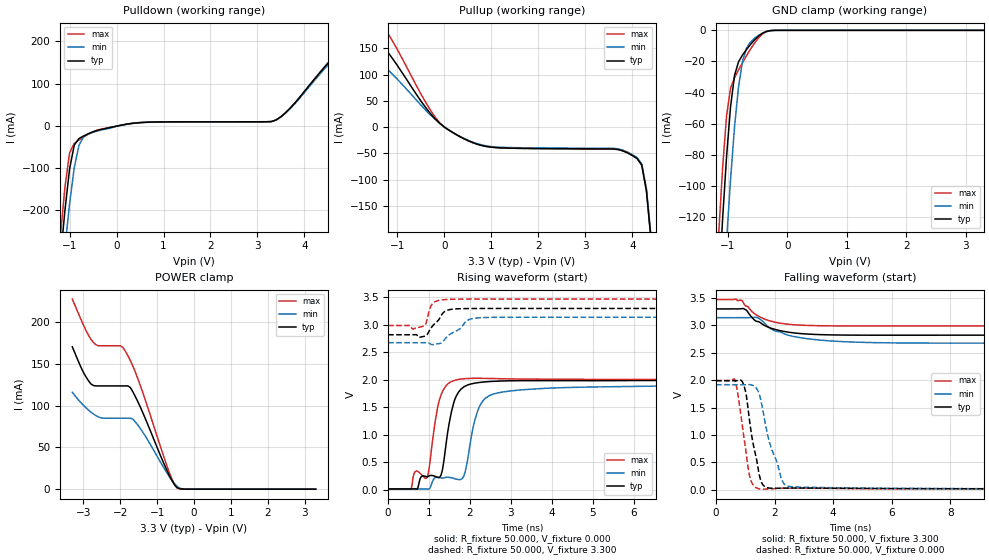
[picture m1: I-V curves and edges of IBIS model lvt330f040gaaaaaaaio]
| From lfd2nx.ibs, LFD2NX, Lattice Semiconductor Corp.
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[Model] lvt330f040gaaaaaaaio
Model_type I/O
Polarity   Non-Inverting
Enable   Active-Low
Vinl =  0.800V
Vinh =  2.000V
Vmeas =  1.650V
Cref =  0.0F
Rref =  1.000M
Vref =  0.0V
C_comp   5.000pF   4.000pF   5.500pF
[Temperature Range]   25.000   0.125k   -40.000
[Voltage Range]   3.300V   3.140V   3.470V
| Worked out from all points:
|   slope of the pulldown table from 0 to 0.495 V, typ, clamps not added: 58.8 ohm
|   slope of the pullup table from 0 to 0.495 V, typ, clamps not added: 19.5 ohm
|   GND clamp passes 1 mA (typ) near -0.37 V on its own axis
|   POWER clamp passes 1 mA (typ) near -0.42 V on its own axis
|   rising waveform, R_fixture 50.000, V_fixture 0.000: 20-80 % time 269ps typ, 342ps min, 236ps max; typ from 0.019 V to 1.99 V
|   rising waveform, R_fixture 50.000, V_fixture 3.300: 20-80 % time 301ps typ, 462ps min, 125ps max; typ from 2.82 V to 3.3 V
|   falling waveform, R_fixture 50.000, V_fixture 3.300: 20-80 % time 937ps typ, 1.3ns min, 836ps max; typ from 3.3 V to 2.82 V
|   falling waveform, R_fixture 50.000, V_fixture 0.000: 20-80 % time 363ps typ, 566ps min, 307ps max; typ from 1.99 V to 0.019 V
[GND_clamp]
|Voltage   I(typ)   I(min)   I(max)
-3.3V     -1.887A    -1.873A    -1.902A
-1.156V   -166.9mA   -224mA     -132.1mA
-1.089V   -121.5mA   -178.4mA   -88.64mA
-1.022V   -81.05mA   -135.2mA   -54.94mA
-955mV    -48.98mA   -95.79mA   -37.15mA
-888mV    -28.98mA   -62.05mA   -30.42mA
-821mV    -20.23mA   -36.35mA   -25.49mA
-754mV    -15.89mA   -19.89mA   -20.81mA
-687mV    -12.34mA   -11.44mA   -16.31mA
-620mV    -9.094mA   -7.515mA   -12.09mA
-419mV    -1.869mA   -1.836mA   -2.383mA
3.3V      0A         0A         0A
[POWER_clamp]
|Voltage   I(typ)   I(min)   I(max)
-3.3V     170.3mA    115.9mA    227.4mA
-2.998V   139.6mA    100.3mA    196.3mA
-2.797V   125.9mA    92.2mA     179.4mA
-2.596V   123.5mA    86.45mA    171.5mA
-1.993V   123.5mA    84.93mA    171.5mA
-1.792V   123.5mA    84.93mA    159.6mA
-1.658V   116.4mA    83.68mA    147.1mA
-1.457V   98.28mA    72.65mA    124.1mA
-720mV    21.08mA    18.41mA    25.96mA
-452mV    1.573mA    3.148mA    1.229mA
-184mV    5.589uA    37.85uA    1.612uA
3.3V      0A         0A         0A
[Pulldown]
|Voltage   I(typ)   I(min)   I(max)
-3.3V     -3.199A    -3.09A     -3.287A
-1.2V     -321.9mA   -406.6mA   -267.9mA
-1.1V     -202.3mA   -291.4mA   -147.1mA
-1V       -102.6mA   -185.6mA   -64.5mA
-900mV    -45.82mA   -99.21mA   -41.48mA
-800mV    -30.11mA   -46.44mA   -33.69mA
-600mV    -18.75mA   -19.13mA   -19.91mA
500mV     7.634mA    7.405mA    7.634mA
3.3V      10.2mA     9.896mA    10.2mA
5V        196.9mA    191mA      196.9mA
6.3V      206.6mA    200.4mA    206.6mA
6.6V      235mA      227.9mA    235mA
[Pullup]
|Voltage   I(typ)   I(min)   I(max)
-3.3V     225.4mA    159.2mA    289.5mA
-3V       191.7mA    142.3mA    256.1mA
-2.6V     172mA      126.6mA    227.2mA
-1.5V     172mA      125.1mA    215.9mA
-1.3V     153.8mA    116.5mA    191.8mA
-200mV    15.97mA    14.98mA    19.28mA
600mV     -29.35mA   -28.47mA   -29.35mA
3.9V      -49.03mA   -47.55mA   -49.03mA
4.2V      -72.01mA   -69.85mA   -72.01mA
4.3V      -121mA     -117.4mA   -121mA
4.4V      -215.8mA   -209.3mA   -215.8mA
6.6V      -3.209A    -3.112A    -3.209A
[Ramp]
| variable   typ   min   max
dV/dt_r   1.182/0.275n   1.138/0.343n   1.192/0.237n
dV/dt_f   0.287/0.944n   0.277/1.301n   0.288/0.844n
R_load = 50.000
[Rising Waveform]
R_fixture = 50.000
V_fixture = 0.000
V_fixture_min = 0.000
V_fixture_max = 0.000
|  time   V(typ)   V(min)   V(max)
0s        19.23mV    18.96mV    17.33mV
950ps     239.8mV    19.5mV     227.4mV
1.27ns    240mV      224.2mV    1.673V
1.63ns    1.645V     205.4mV    1.994V
1.85ns    1.874V     257.1mV    2.022V
2.07ns    1.935V     1.113V     2.03V
2.32ns    1.962V     1.624V     2.03V
2.78ns    1.981V     1.779V     2.022V
8.46ns    1.994V     1.902V     2.008V
200ns     1.989V     1.916V     1.996V
[Rising Waveform]
R_fixture = 50.000
V_fixture = 3.300
V_fixture_min = 3.140
V_fixture_max = 3.470
|  time   V(typ)   V(min)   V(max)
0s        2.822V     2.678V     2.99V
530ps     2.822V     2.678V     2.992V
600ps     2.822V     2.678V     2.925V
880ps     2.792V     2.678V     2.982V
930ps     2.807V     2.678V     3.04V
1.05ns    2.945V     2.647V     3.349V
1.28ns    3.148V     2.666V     3.451V
1.45ns    3.268V     2.793V     3.463V
1.96ns    3.298V     3.091V     3.47V
200ns     3.3V       3.14V      3.47V
[Falling Waveform]
R_fixture = 50.000
V_fixture = 3.300
V_fixture_min = 3.140
V_fixture_max = 3.470
|  time   V(typ)   V(min)   V(max)
0s        3.3V       3.14V      3.47V
680ps     3.3V       3.139V     3.479V
870ps     3.304V     3.141V     3.457V
950ps     3.303V     3.141V     3.398V
1.44ns    3.068V     3.134V     3.17V
1.99ns    2.929V     2.903V     3.061V
2.79ns    2.855V     2.783V     3.007V
4.09ns    2.825V     2.71V      2.99V
8.26ns    2.821V     2.675V     2.99V
200ns     2.822V     2.678V     2.99V
[Falling Waveform]
R_fixture = 50.000
V_fixture = 0.000
V_fixture_min = 0.000
V_fixture_max = 0.000
|  time   V(typ)   V(min)   V(max)
0s        1.99V      1.916V     1.996V
640ps     1.99V      1.915V     2.01V
910ps     1.961V     1.916V     1.125V
1.2ns     1.056V     1.916V     159.1mV
1.43ns    415.4mV    1.806V     24.54mV
1.6ns     93.72mV    1.453V     12.06mV
1.83ns    31.38mV    857.1mV    16.57mV
2.32ns    30.7mV     107.4mV    29.64mV
4.53ns    26.53mV    35.5mV     22.52mV
200ns     18.98mV    18.96mV    17.12mV
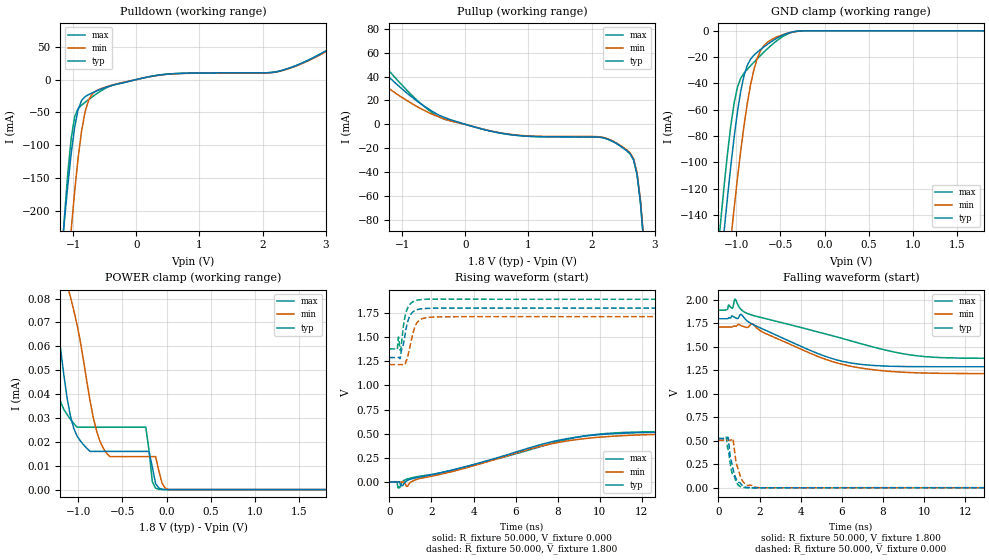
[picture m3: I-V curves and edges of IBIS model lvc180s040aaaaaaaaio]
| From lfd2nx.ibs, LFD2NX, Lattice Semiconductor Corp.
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[Model] lvc180s040aaaaaaaaio
Model_type I/O
Polarity   Non-Inverting
Enable   Active-Low
Vinl =  0.630V
Vinh =  1.170V
Vmeas =  0.900V
Cref =  0.0F
Rref =  1.000M
Vref =  0.0V
C_comp   5.000pF   4.000pF   5.500pF
[Temperature Range]   25.000   0.125k   -40.000
[Voltage Range]   1.800V   1.710V   1.890V
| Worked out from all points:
|   slope of the pulldown table from 0 to 0.27 V, typ, clamps not added: 48.7 ohm
|   slope of the pullup table from 0 to 0.27 V, typ, clamps not added: 66.8 ohm
|   GND clamp passes 1 mA (typ) near -0.37 V on its own axis
|   rising waveform, R_fixture 50.000, V_fixture 0.000: 20-80 % time 5.14ns typ, 5.06ns min, 5.46ns max; typ from 0 V to 0.523 V
|   rising waveform, R_fixture 50.000, V_fixture 1.800: 20-80 % time 317ps typ, 338ps min, 247ps max; typ from 1.29 V to 1.8 V
|   falling waveform, R_fixture 50.000, V_fixture 1.800: 20-80 % time 3.23ns typ, 3.42ns min, 5.34ns max; typ from 1.8 V to 1.29 V
|   falling waveform, R_fixture 50.000, V_fixture 0.000: 20-80 % time 309ps typ, 328ps min, 349ps max; typ from 0.523 V to 0 V
[GND_clamp]
|Voltage   I(typ)   I(min)   I(max)
-1.8V     -665.5mA   -701.9mA   -644.7mA
-1.208V   -203.2mA   -259.3mA   -168.6mA
-1.171V   -176.5mA   -233.3mA   -141.8mA
-1.134V   -150.7mA   -207.7mA   -116.3mA
-1.06V    -102.3mA   -158.3mA   -71.8mA
-1.023V   -80.78mA   -134.8mA   -54.83mA
-986mV    -61.78mA   -112.4mA   -42.93mA
-875mV    -26.33mA   -55.53mA   -29.29mA
-764mV    -16.38mA   -21.41mA   -21.4mA
-616mV    -8.858mA   -7.288mA   -11.79mA
-283mV    -142.7uA   -287uA     -113.6uA
1.8V      1.806nA    0A         -451.7pA
[POWER_clamp]
|Voltage   I(typ)   I(min)   I(max)
-1.8V     186.1uA    259.3uA    183.5uA
-1.382V   94.44uA    136.9uA    91.49uA
-1.345V   89.56uA    127.8uA    77.5uA
-1.308V   84.02uA    119.2uA    62.8uA
-1.234V   68.87uA    103.6uA    41.99uA
-1.086V   30.66uA    80.57uA    29.36uA
-864mV    15.99uA    36.92uA    26.17uA
-642mV    15.99uA    13.83uA    26.17uA
-235mV    15.99uA    13.83uA    26.17uA
-161mV    9.477uA    13.83uA    3.316uA
24mV      0A         0A         261.1pA
1.8V      0A         0A         0A
[Pulldown]
|Voltage   I(typ)   I(min)   I(max)
-1.8V     -995.9mA   -1.248A    -1.252A
-1.195V   -277.5mA   -429.4mA   -291.1mA
-1.14V    -218.4mA   -360mA     -213.9mA
-1.03V    -112.8mA   -229.5mA   -89.71mA
-975mV    -72.73mA   -170.7mA   -56.82mA
-920mV    -45.76mA   -119.3mA   -44.24mA
-865mV    -31.82mA   -78.24mA   -38.99mA
-755mV    -23mA      -31.77mA   -30.61mA
-535mV    -13.67mA   -13.02mA   -15.89mA
290mV     5.876mA    5.699mA    5.876mA
2.27V     13.04mA    12.65mA    13.04mA
3.6V      77.31mA    74.99mA    77.31mA
[Pullup]
|Voltage   I(typ)   I(min)   I(max)
-1.8V     69.64mA    52.58mA    81.3mA
-910mV    25.55mA    19.41mA    27.74mA
-415mV    7.654mA    6.149mA    6.163mA
630mV     -8.033mA   -7.792mA   -8.033mA
2.115V    -10.77mA   -10.45mA   -10.77mA
2.335V    -14.38mA   -13.95mA   -14.38mA
2.555V    -22.02mA   -21.36mA   -22.02mA
2.665V    -29.69mA   -28.8mA    -29.69mA
2.72V     -41.99mA   -40.73mA   -41.99mA
2.775V    -65.96mA   -63.98mA   -65.96mA
2.83V     -101.9mA   -98.8mA    -101.9mA
3.6V      -893.2mA   -866.4mA   -893.2mA
[Ramp]
| variable   typ   min   max
dV/dt_r   0.314/5.142n   0.305/5.063n   0.315/5.456n
dV/dt_f   0.307/3.233n   0.292/3.426n   0.308/5.337n
R_load = 50.000
[Rising Waveform]
R_fixture = 50.000
V_fixture = 0.000
V_fixture_min = 0.000
V_fixture_max = 0.000
|  time   V(typ)   V(min)   V(max)
0s        55.76uV    -541.6uV   144.1uV
354ps     -420nV     -811uV     1.746mV
407ps     201.3uV    -848.3uV   -58.2mV
481ps     -1.924mV   -614.8uV   -59.5mV
609ps     -39.04mV   -345uV     -460uV
844ps     15.36mV    -45.3mV    31.01mV
1.355ns   47.73mV    31.55mV    56.92mV
7ns       375.4mV    360.4mV    354.7mV
9.719ns   485.6mV    459.1mV    489.7mV
20ns      522.7mV    504.7mV    524.5mV
[Rising Waveform]
R_fixture = 50.000
V_fixture = 1.800
V_fixture_min = 1.710
V_fixture_max = 1.890
|  time   V(typ)   V(min)   V(max)
0s        1.289V     1.215V     1.378V
371ps     1.289V     1.215V     1.375V
429ps     1.289V     1.215V     1.501V
520ps     1.29V      1.215V     1.362V
744ps     1.527V     1.215V     1.716V
859ps     1.652V     1.291V     1.798V
998ps     1.73V      1.427V     1.845V
1.214ns   1.775V     1.608V     1.875V
1.504ns   1.792V     1.686V     1.888V
20ns      1.8V       1.712V     1.892V
[Falling Waveform]
R_fixture = 50.000
V_fixture = 1.800
V_fixture_min = 1.710
V_fixture_max = 1.890
|  time   V(typ)   V(min)   V(max)
0s        1.8V       1.712V     1.892V
674ps     1.829V     1.713V     1.912V
811ps     1.812V     1.721V     2.009V
1.1ns     1.846V     1.727V     1.898V
1.492ns   1.761V     1.72V      1.848V
1.652ns   1.741V     1.745V     1.837V
5.003ns   1.415V     1.384V     1.649V
6.83ns    1.316V     1.278V     1.54V
10.47ns   1.289V     1.22V      1.39V
20ns      1.289V     1.215V     1.378V
[Falling Waveform]
R_fixture = 50.000
V_fixture = 0.000
V_fixture_min = 0.000
V_fixture_max = 0.000
|  time   V(typ)   V(min)   V(max)
0s        522.7mV    504.7mV    524.5mV
367ps     522.3mV    504.3mV    540mV
472ps     530.7mV    504.4mV    405.7mV
580ps     321.1mV    504.8mV    244.9mV
694ps     214.1mV    521.9mV    135.5mV
872ps     87.55mV    253.7mV    60.07mV
1.082ns   43.07mV    111.3mV    10.88mV
1.262ns   10.06mV    46.43mV    1.455mV
2.193ns   -442.4uV   -843.4uV   -1.377mV
20ns      55.76uV    -541.6uV   144.1uV
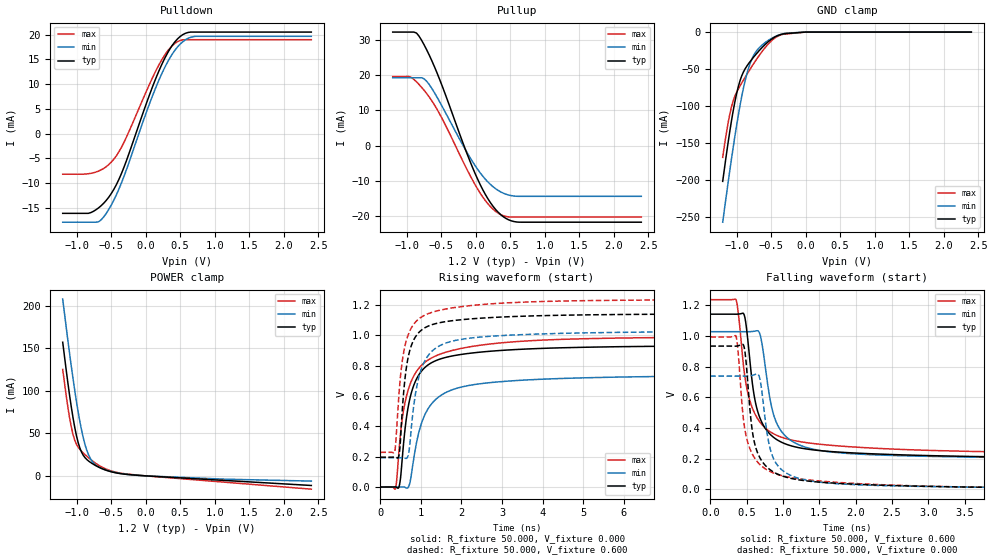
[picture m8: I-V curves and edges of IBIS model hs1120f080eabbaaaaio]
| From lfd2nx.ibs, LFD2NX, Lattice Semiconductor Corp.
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|Model hs1120f080eabbaaaaio
[Model] hs1120f080eabbaaaaio
| Clamp models do not include dynamic input termination. Please refer to
| the hs1120axxxeabbaaaain model for input termination.
Model_type I/O
Polarity   Non-Inverting
Enable   Active-Low
Vinl =  0.500V
Vinh =  0.700V
Vmeas =  0.600V
Cref =  20.000pF
Rref =  50.000
Vref =  0.600V
C_comp   5.000pF   4.000pF   5.500pF
[Temperature Range]   25.000   0.125k   -40.000
[Voltage Range]   1.200V   1.140V   1.260V
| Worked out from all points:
|   slope of the pulldown table from 0 to 0.18 V, typ, clamps not added: 27.3 ohm
|   slope of the pullup table from 0 to 0.18 V, typ, clamps not added: 26.1 ohm
|   GND clamp passes 1 mA (typ) near -0.14 V on its own axis
|   POWER clamp passes 1 mA (typ) near -0.17 V on its own axis
|   rising waveform, R_fixture 50.000, V_fixture 0.000: 20-80 % time 431ps typ, 626ps min, 545ps max; typ from 0 V to 0.934 V
|   rising waveform, R_fixture 50.000, V_fixture 0.600: 20-80 % time 284ps typ, 413ps min, 327ps max; typ from 0.197 V to 1.14 V
|   falling waveform, R_fixture 50.000, V_fixture 0.600: 20-80 % time 253ps typ, 270ps min, 285ps max; typ from 1.14 V to 0.197 V
|   falling waveform, R_fixture 50.000, V_fixture 0.000: 20-80 % time 198ps typ, 218ps min, 217ps max; typ from 0.934 V to 0 V
[Pulldown]
|Voltage   I(typ)   I(min)   I(max)
-1.2V     -16.15mA   -17.94mA   -8.219mA
-793mV    -16mA      -17.94mA   -8.053mA
-682mV    -15.05mA   -17.87mA   -7.595mA
-571mV    -13.55mA   -16.18mA   -6.715mA
-460mV    -11.3mA    -13.49mA   -5.195mA
-349mV    -8.077mA   -9.972mA   -2.767mA
21mV      6.472mA    4.689mA    8.875mA
206mV     13.1mA     11.24mA    14.23mA
354mV     17.17mA    15.36mA    17.32mA
502mV     19.67mA    18.13mA    18.86mA
724mV     20.55mA    19.68mA    19.01mA
2.4V      20.55mA    19.69mA    19.01mA
[Pullup]
|Voltage   I(typ)   I(min)   I(max)
-1.2V     32.18mA    19.26mA    19.61mA
-930mV    32.18mA    19.26mA    19.34mA
-856mV    31.91mA    19.26mA    18.1mA
-782mV    29.87mA    19.26mA    16.56mA
-671mV    25.67mA    17.33mA    13.8mA
-523mV    18.91mA    12.54mA    9.103mA
-153mV    -749.4uA   -894uA     -5.584mA
32mV      -9.535mA   -6.72mA    -12.3mA
217mV     -16.14mA   -10.96mA   -17.24mA
402mV     -20.07mA   -13.4mA    -19.78mA
624mV     -21.6mA    -14.29mA   -20.15mA
2.4V      -21.61mA   -14.29mA   -20.15mA
[GND_clamp]
|Voltage   I(typ)   I(min)   I(max)
-1.2V     -201.8mA   -257mA     -169.4mA
-1.125V   -151.4mA   -205.6mA   -124.4mA
-1.05V    -107.4mA   -157mA     -93.36mA
-975mV    -74.07mA   -112.9mA   -77.04mA
-925mV    -59.28mA   -87.24mA   -68.87mA
-875mV    -49.6mA    -65.58mA   -61.06mA
-825mV    -42.58mA   -48.49mA   -53.44mA
-750mV    -33.57mA   -31.23mA   -42.41mA
-600mV    -18.06mA   -15.21mA   -22.68mA
-375mV    -3.74mA    -3.594mA   -4.332mA
0V        0A         0A         0A
2.4V      0A         0A         0A
[POWER_clamp]
|Voltage   I(typ)   I(min)   I(max)
-1.2V     156.9mA    207.6mA    125mA
-1.125V   109.1mA    159mA      80.51mA
-1.075V   80.57mA    128.3mA    57.13mA
-1.025V   56.63mA    99.87mA    41.73mA
-975mV    38.74mA    74.4mA     33.51mA
-900mV    23.86mA    43.88mA    26.68mA
-850mV    19.08mA    29.7mA     22.97mA
-775mV    14.57mA    17.25mA    17.9mA
-700mV    11.09mA    11.42mA    13.53mA
-450mV    3.875mA    4.163mA    4.676mA
-125mV    735.3uA    624.3uA    974.1uA
2.4V      -11.3mA    -6.156mA   -15.63mA
[Ramp]
| variable   typ   min   max
dV/dt_r   0.560/0.431n   0.443/0.629n   0.596/0.546n
dV/dt_f   0.523/0.375n   0.493/0.385n   0.533/0.474n
R_load = 50.000
[Rising Waveform]
R_fixture = 50.000
V_fixture = 0.000
V_fixture_min = 0.000
V_fixture_max = 0.000
|  time   V(typ)   V(min)   V(max)
0s        56.54uV    72.08uV    44.61uV
371ps     901.7uV    136.4uV    -12.4mV
457ps     -1.722mV   158.3uV    224.4mV
557ps     236.2mV    722.1uV    476.9mV
706ps     552.5mV    7.419mV    654.7mV
906ps     718.1mV    308.4mV    766.2mV
1.086ns   783.5mV    468.4mV    818.2mV
1.386ns   834mV      581.6mV    865.5mV
2.566ns   890.7mV    683.4mV    937.2mV
30ns      934.1mV    738.4mV    994mV
[Rising Waveform]
R_fixture = 50.000
V_fixture = 0.600
V_fixture_min = 0.571
V_fixture_max = 0.631
|  time   V(typ)   V(min)   V(max)
0s        196.7mV    192.5mV    228.3mV
354ps     197.1mV    192.6mV    229.9mV
457ps     203.8mV    192.7mV    596.5mV
617ps     732.4mV    189.4mV    938.4mV
697ps     866.1mV    218.9mV    1.008V
767ps     932.5mV    394mV      1.048V
917ps     1.007V     684.5mV    1.099V
1.147ns   1.055V     853mV      1.138V
2.081ns   1.104V     976mV      1.19V
30ns      1.143V     1.028V     1.238V
[Falling Waveform]
R_fixture = 50.000
V_fixture = 0.600
V_fixture_min = 0.571
V_fixture_max = 0.631
|  time   V(typ)   V(min)   V(max)
0s        1.143V     1.028V     1.238V
356ps     1.142V     1.028V     1.235V
466ps     1.139V     1.028V     768.9mV
607ps     601.2mV    1.031V     498.5mV
670ps     481mV      1.027V     446.3mV
721ps     425.1mV    919.6mV    416mV
851ps     346mV      520.8mV    366.7mV
990ps     304.1mV    369.9mV    337.5mV
1.88ns    238.8mV    233.5mV    278.2mV
30ns      196.7mV    192.5mV    228.3mV
[Falling Waveform]
R_fixture = 50.000
V_fixture = 0.000
V_fixture_min = 0.000
V_fixture_max = 0.000
|  time   V(typ)   V(min)   V(max)
0s        934.1mV    738.4mV    994mV
356ps     933.9mV    738mV      995.9mV
456ps     941.8mV    738.1mV    457mV
486ps     860.9mV    737.8mV    363.5mV
576ps     386.5mV    742.7mV    231.1mV
660ps     226.7mV    748.4mV    172mV
801ps     134.9mV    311.1mV    120.4mV
910ps     101.7mV    165.5mV    98.61mV
1.751ns   38.07mV    35.24mV    44.32mV
30ns      56.54uV    72.08uV    44.61uV
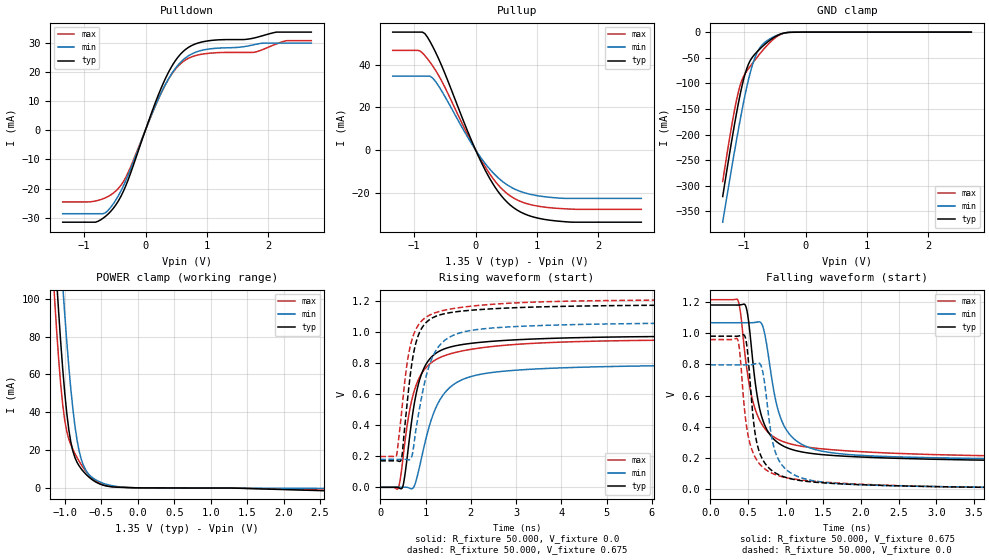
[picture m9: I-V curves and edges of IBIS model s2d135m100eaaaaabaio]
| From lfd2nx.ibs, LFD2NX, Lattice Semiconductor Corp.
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|Model s2d135m100eaaaaabaio
[Model] s2d135m100eaaaaabaio
Model_type I/O
Polarity   Non-Inverting
Enable   Active-Low
Vinl =  0.575V
Vinh =  0.775V
Vmeas =  0.675V
Cref =  30.000pF
Rref =  50.000
Vref =  0.675V
C_comp   5.000pF   4.000pF   5.500pF
[Temperature Range]   25.000   0.125k   -40.000
[Voltage Range]   1.350V   1.280V   1.420V
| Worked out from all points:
|   slope of the pulldown table from 0 to 0.203 V, typ, clamps not added: 17.4 ohm
|   slope of the pullup table from 0 to 0.203 V, typ, clamps not added: 16.9 ohm
|   GND clamp passes 1 mA (typ) near -0.31 V on its own axis
|   POWER clamp passes 1 mA (typ) near -0.43 V on its own axis
|   rising waveform, R_fixture 50.000, V_fixture 0.0: 20-80 % time 397ps typ, 623ps min, 491ps max; typ from 0 V to 0.981 V
|   rising waveform, R_fixture 50.000, V_fixture 0.675: 20-80 % time 303ps typ, 464ps min, 333ps max; typ from 0.171 V to 1.18 V
|   falling waveform, R_fixture 50.000, V_fixture 0.675: 20-80 % time 230ps typ, 281ps min, 276ps max; typ from 1.18 V to 0.172 V
|   falling waveform, R_fixture 50.000, V_fixture 0.0: 20-80 % time 176ps typ, 212ps min, 199ps max; typ from 0.981 V to 0 V
[Pulldown]
|Voltage   I(typ)   I(min)   I(max)
-1.35V    -31.52mA   -28.61mA   -24.57mA
-817mV    -31.52mA   -28.61mA   -24.26mA
-653mV    -29.52mA   -28.27mA   -23.15mA
-489mV    -25.73mA   -24.06mA   -20.91mA
-284mV    -17.01mA   -15.39mA   -14.5mA
290mV     16.19mA    14.33mA    14.27mA
454mV     22.83mA    20.27mA    20.05mA
659mV     27.8mA     24.92mA    24.18mA
1.069V    30.75mA    27.92mA    26.43mA
1.766V    31.59mA    29.29mA    26.68mA
2.299V    33.62mA    29.85mA    30.69mA
2.7V      33.62mA    29.85mA    30.69mA
[Pullup]
|Voltage   I(typ)   I(min)   I(max)
-1.35V    55.32mA    34.66mA    46.74mA
-908mV    55.32mA    34.66mA    46.54mA
-785mV    52.99mA    34.66mA    42.83mA
-703mV    48.79mA    33.84mA    39.62mA
-621mV    43.98mA    30.83mA    35.9mA
-88mV     5.888mA    4.039mA    4.858mA
117mV     -7.248mA   -4.887mA   -6.056mA
363mV     -19.41mA   -12.97mA   -16.28mA
609mV     -26.91mA   -17.99mA   -22.42mA
896mV     -31.1mA    -20.88mA   -25.7mA
1.265V    -33.2mA    -22.4mA    -27.29mA
2.7V      -33.94mA   -22.78mA   -27.9mA
[GND_clamp]
|Voltage   I(typ)   I(min)   I(max)
-1.35V    -320.9mA   -371mA     -291.7mA
-1.21V    -216.8mA   -269.5mA   -187.2mA
-1.126V   -159mA     -211.3mA   -133.3mA
-1.07V    -124.2mA   -174.2mA   -105.6mA
-986mV    -81.78mA   -122.8mA   -81.18mA
-902mV    -55.61mA   -79.36mA   -66.72mA
-818mV    -41.95mA   -47.73mA   -53.44mA
-734mV    -31.67mA   -28.77mA   -40.78mA
-650mV    -22.47mA   -18.69mA   -29.01mA
-454mV    -6.221mA   -5.753mA   -7.69mA
-286mV    -734.4uA   -759.2uA   -785.5uA
2.7V      0A         0A         0A
[POWER_clamp]
|Voltage   I(typ)   I(min)   I(max)
-1.35V    276.5mA    320.5mA    251mA
-1.142V   128.3mA    176.6mA    100.9mA
-1.114V   110.5mA    158.5mA    83.9mA
-1.086V   93.5mA     140.9mA    68.53mA
-1.03V    63.21mA    107.6mA    44.18mA
-1.002V   50.42mA    92.11mA    35.83mA
-946mV    30.82mA    64.28mA    25.76mA
-834mV    13.57mA    25.52mA    16.1mA
-750mV    8.839mA    12.31mA    10.8mA
-610mV    3.896mA    5.035mA    4.505mA
-78mV     75.17uA    92.3uA     98.29uA
2.7V      -1.695mA   -291.3uA   -1.333mA
[Ramp]
| variable   typ   min   max
dV/dt_r   0.588/0.398n   0.478/0.627n   0.576/0.491n
dV/dt_f   0.587/0.340n   0.536/0.410n   0.587/0.469n
R_load = 50.000
[Rising Waveform]
R_fixture= 50.000
V_fixture= 0.0
V_fixture_min= 0.0
V_fixture_max= 0.0
|time   V(typ)   V(min)   V(max)
0s        5.449uV    216.2uV    716.2nV
388ps     236.2uV    246.9uV    -9.1mV
497ps     4.218mV    457.3uV    176.6mV
716ps     473.8mV    -6.764mV   586.6mV
866ps     690.8mV    130.8mV    709.4mV
1.046ns   810.6mV    356.2mV    784mV
1.412ns   893.1mV    605.5mV    848.8mV
2.106ns   932.7mV    722.8mV    895.3mV
7.414ns   975.6mV    788.7mV    952.2mV
30ns      980.8mV    796.6mV    959.3mV
[Rising Waveform]
R_fixture= 50.000
V_fixture= 0.675
V_fixture_min= 0.642
V_fixture_max= 0.710
|time   V(typ)   V(min)   V(max)
0s        171.1mV    180.5mV    198.9mV
351ps     171.5mV    180.5mV    199.5mV
467ps     183.8mV    180.6mV    473.2mV
578ps     497.9mV    179.5mV    769.7mV
687ps     778.3mV    191.6mV    939.6mV
797ps     942.3mV    390.4mV    1.026V
1.147ns   1.093V     836.3mV    1.119V
1.724ns   1.135V     993.5mV    1.159V
6.767ns   1.176V     1.06V      1.209V
30ns      1.181V     1.067V     1.215V
[Falling Waveform]
R_fixture= 50.000
V_fixture= 0.675
V_fixture_min= 0.642
V_fixture_max= 0.710
|time   V(typ)   V(min)   V(max)
0s        1.181V     1.068V     1.215V
362ps     1.181V     1.068V     1.216V
406ps     1.183V     1.068V     1.114V
467ps     1.179V     1.068V     837.2mV
630ps     578.2mV    1.073V     469.4mV
737ps     395.6mV    960.1mV    381.6mV
864ps     311.5mV    579.6mV    329.2mV
994ps     271.1mV    393.4mV    300.7mV
1.654ns   215.5mV    231mV      251.7mV
30ns      171.7mV    181.2mV    199.4mV
[Falling Waveform]
R_fixture= 50.000
V_fixture= 0.0
V_fixture_min= 0.0
V_fixture_max= 0.0
|time   V(typ)   V(min)   V(max)
0s        981.4mV    797.6mV    959.8mV
362ps     981.4mV    797.3mV    960.8mV
457ps     984.1mV    797.4mV    499.9mV
577ps     423.5mV    801.6mV    223.6mV
647ps     245.5mV    808.3mV    166.8mV
704ps     182.9mV    733.9mV    137.9mV
824ps     117.2mV    312.2mV    101.4mV
914ps     91.73mV    182.7mV    85.44mV
1.524ns   40.09mV    43.46mV    45.16mV
30ns      482.1uV    803.1uV    327.3uV
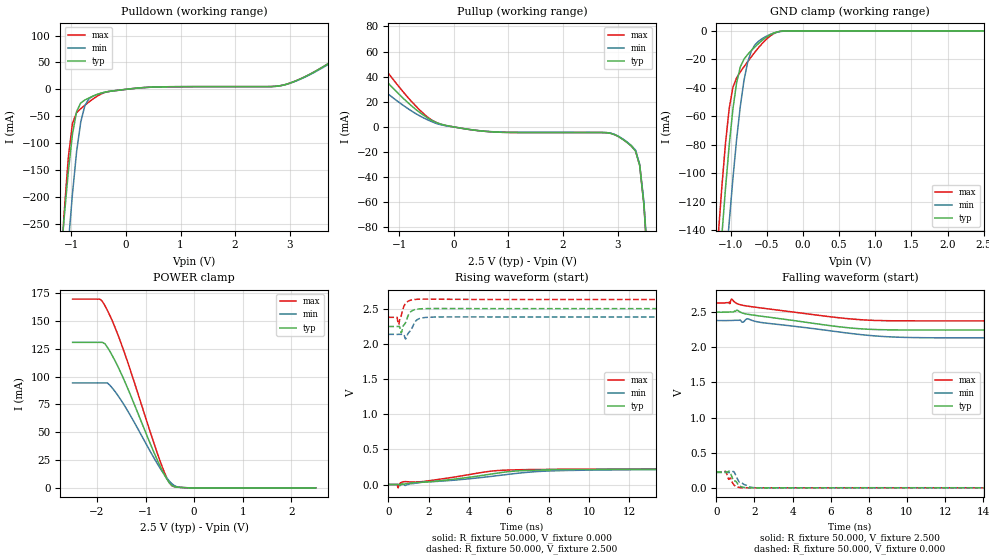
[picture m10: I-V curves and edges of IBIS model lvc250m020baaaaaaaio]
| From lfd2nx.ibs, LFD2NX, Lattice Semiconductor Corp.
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[Model] lvc250m020baaaaaaaio
Model_type I/O
Polarity   Non-Inverting
Enable   Active-Low
Vinl =  0.700V
Vinh =  1.700V
Vmeas =  1.250V
Cref =  0.0F
Rref =  1.000M
Vref =  0.0V
C_comp   5.000pF   4.000pF   5.500pF
[Temperature Range]   25.000   0.125k   -40.000
[Voltage Range]   2.500V   2.380V   2.630V
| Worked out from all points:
|   slope of the pulldown table from 0 to 0.375 V, typ, clamps not added: 103 ohm
|   slope of the pullup table from 0 to 0.375 V, typ, clamps not added: 145 ohm
|   GND clamp passes 1 mA (typ) near -0.37 V on its own axis
|   POWER clamp passes 1 mA (typ) near -0.40 V on its own axis
|   rising waveform, R_fixture 50.000, V_fixture 0.000: 20-80 % time 3.61ns typ, 4.57ns min, 3.04ns max; typ from 0 V to 0.224 V
|   rising waveform, R_fixture 50.000, V_fixture 2.500: 20-80 % time 243ps typ, 302ps min, 209ps max; typ from 2.25 V to 2.5 V
|   falling waveform, R_fixture 50.000, V_fixture 2.500: 20-80 % time 4.11ns typ, 4.45ns min, 4.41ns max; typ from 2.5 V to 2.25 V
|   falling waveform, R_fixture 50.000, V_fixture 0.000: 20-80 % time 364ps typ, 460ps min, 341ps max; typ from 0.224 V to 0 V
[GND_clamp]
|Voltage   I(typ)   I(min)   I(max)
-2.5V     -1.233A    -1.246A    -1.23A
-1.174V   -179.1mA   -235.9mA   -144.4mA
-1.123V   -143.6mA   -200.7mA   -109.5mA
-1.072V   -110.2mA   -166.6mA   -78.57mA
-1.021V   -80.08mA   -134.1mA   -54.34mA
-970mV    -54.89mA   -103.7mA   -39.63mA
-919mV    -36.41mA   -76.3mA    -32.99mA
-817mV    -19.89mA   -34.81mA   -25.2mA
-715mV    -13.78mA   -14.11mA   -18.16mA
-511mV    -4.596mA   -3.904mA   -6.102mA
-256mV    -63.21uA   -177.9uA   -38.32uA
2.5V      -23.56nA   0A         -150.9nA
[POWER_clamp]
|Voltage   I(typ)   I(min)   I(max)
-2.5V     130.9mA    94.41mA    169.8mA
-1.937V   130.9mA    94.41mA    169.8mA
-1.835V   129.6mA    94.41mA    163.9mA
-1.733V   122.8mA    92.29mA    155mA
-1.478V   100.7mA    77.18mA    127mA
-866mV    35.87mA    29.9mA     45.33mA
-662mV    16.03mA    15.02mA    19.46mA
-560mV    7.73mA     8.668mA    8.662mA
-458mV    2.143mA    3.687mA    1.896mA
-356mV    647.1uA    1.015mA    754.8uA
-101mV    23.95uA    66.65uA    14.28uA
2.5V      0A         0A         0A
[Pulldown]
|Voltage   I(typ)   I(min)   I(max)
-2.5V     -2.133A    -2.495A    -2.742A
-1.208V   -333.8mA   -498mA     -352.8mA
-1.132V   -239.3mA   -390.6mA   -230.6mA
-1.056V   -153.2mA   -288.4mA   -127.1mA
-980mV    -83.55mA   -194.8mA   -63.14mA
-904mV    -41.24mA   -116.1mA   -43.39mA
-828mV    -25.25mA   -60.49mA   -36.06mA
-752mV    -19.86mA   -30.04mA   -29.54mA
-600mV    -12.47mA   -12.35mA   -17.57mA
312mV     3.206mA    3.11mA     3.206mA
2.896V    8.243mA    7.995mA    8.243mA
5V        113.2mA    109.8mA    113.2mA
[Pullup]
|Voltage   I(typ)   I(min)   I(max)
-2.5V     80.2mA     62.08mA    100mA
-2.22V    77mA       58.13mA    96mA
-1.84V    64.02mA    48.16mA    79mA
-776mV    16.78mA    12.7mA     20.26mA
-244mV    2.321mA    1.813mA    2.153mA
668mV     -3.822mA   -3.707mA   -3.822mA
2.948V    -6.19mA    -6.005mA   -6.19mA
3.328V    -19.09mA   -18.52mA   -19.09mA
3.404V    -30.57mA   -29.66mA   -30.57mA
3.48V     -61.09mA   -59.26mA   -61.09mA
3.556V    -111.5mA   -108.2mA   -111.5mA
5V        -1.548A    -1.502A    -1.548A
[Ramp]
| variable   typ   min   max
dV/dt_r   0.134/3.609n   0.134/4.601n   0.139/3.045n
dV/dt_f   0.152/4.110n   0.142/4.459n   0.153/4.415n
R_load = 50.000
[Rising Waveform]
R_fixture = 50.000
V_fixture = 0.000
V_fixture_min = 0.000
V_fixture_max = 0.000
|  time   V(typ)   V(min)   V(max)
0s        57.57uV    336.8uV    159.8uV
434ps     71.13uV    168.8uV    2.39mV
486ps     99.73uV    269.9uV    -47.57mV
598ps     -14.38mV   359.9uV    21mV
667ps     9.797mV    394.6uV    30.95mV
765ps     2.681mV    -212.4uV   39.46mV
1.765ns   32.96mV    34.58mV    44.06mV
5.88ns    179mV      141.5mV    204.7mV
8.89ns    211.7mV    199.4mV    216.7mV
20ns      223.6mV    217.3mV    223.7mV
[Rising Waveform]
R_fixture = 50.000
V_fixture = 2.500
V_fixture_min = 2.380
V_fixture_max = 2.630
|  time   V(typ)   V(min)   V(max)
0s        2.246V     2.134V     2.376V
425ps     2.246V     2.134V     2.379V
505ps     2.246V     2.134V     2.275V
566ps     2.24V      2.134V     2.345V
647ps     2.157V     2.135V     2.405V
731ps     2.25V      2.136V     2.498V
865ps     2.307V     2.07V      2.576V
1.098ns   2.451V     2.186V     2.619V
1.495ns   2.494V     2.352V     2.633V
20ns      2.5V       2.381V     2.63V
[Falling Waveform]
R_fixture = 50.000
V_fixture = 2.500
V_fixture_min = 2.380
V_fixture_max = 2.630
|  time   V(typ)   V(min)   V(max)
0s        2.5V       2.381V     2.63V
714ps     2.503V     2.381V     2.622V
804ps     2.503V     2.381V     2.686V
1.095ns   2.528V     2.384V     2.621V
1.385ns   2.487V     2.357V     2.598V
1.682ns   2.469V     2.403V     2.584V
2.501ns   2.438V     2.348V     2.555V
8.14ns    2.255V     2.166V     2.384V
10.86ns   2.246V     2.136V     2.376V
20ns      2.246V     2.134V     2.376V
[Falling Waveform]
R_fixture = 50.000
V_fixture = 0.000
V_fixture_min = 0.000
V_fixture_max = 0.000
|  time   V(typ)   V(min)   V(max)
0s        223.6mV    217.3mV    223.7mV
487ps     223mV      217.2mV    234.1mV
647ps     234.8mV    217mV      122.6mV
694ps     232.5mV    217.2mV    129.8mV
757ps     199.9mV    219.4mV    133.8mV
904ps     102.9mV    231.2mV    48.32mV
1.194ns   32.75mV    85.6mV     4.981mV
1.405ns   7.179mV    56.17mV    9.343uV
2.355ns   -582.3uV   -265.5uV   -979.7uV
20ns      57.57uV    336.8uV    159.8uV
